VERSION 5.8 ;
BUSBITCHARS "[]" ;
DIVIDERCHAR "/" ;
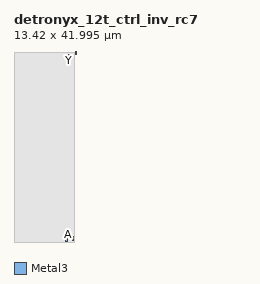
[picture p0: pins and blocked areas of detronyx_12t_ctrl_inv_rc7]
MACRO detronyx_12t_ctrl_inv_rc7
  CLASS BLOCK ;
  FOREIGN detronyx_12t_ctrl_inv_rc7 0.000 0.000 ;
  ORIGIN 0.000 0.000 ;
  SIZE 13.420000 BY 41.995000 ;
  SYMMETRY X Y ;
  PIN VDD
    DIRECTION INOUT ;
    USE POWER ;
    PORT
      LAYER Metal3 ;
        RECT 12.140000 40.295000 12.500000 41.495000 ;
    END
  END VDD
  PIN VSS
    DIRECTION INOUT ;
    USE GROUND ;
    PORT
      LAYER Metal3 ;
        RECT 11.440000 0.200000 11.800000 1.400000 ;
    END
  END VSS
  PIN A
    DIRECTION INPUT ;
    USE SIGNAL ;
    PORT
      LAYER Metal3 ;
        RECT 12.840000 0.400000 13.200000 1.200000 ;
    END
  END A
  PIN Y
    DIRECTION OUTPUT ;
    USE SIGNAL ;
    PORT
      LAYER Metal3 ;
        RECT 13.540000 41.395000 13.900000 42.195000 ;
    END
  END Y
  OBS
    LAYER Metal1 ;
      RECT 0.000000 0.000000 13.420000 41.995000 ;
    LAYER Metal2 ;
      RECT 0.000000 0.000000 13.420000 41.995000 ;
  END
END detronyx_12t_ctrl_inv_rc7
END LIBRARY
